VERSION 5.7 ;
  NOWIREEXTENSIONATPIN ON ;
  DIVIDERCHAR "/" ;
  BUSBITCHARS "[]" ;
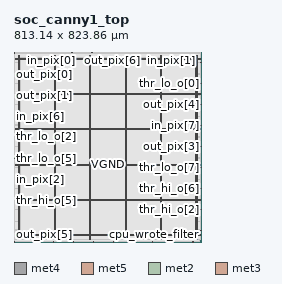
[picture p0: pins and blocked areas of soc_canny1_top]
MACRO soc_canny1_top
  CLASS BLOCK ;
  FOREIGN soc_canny1_top ;
  ORIGIN 0.000 0.000 ;
  SIZE 813.140 BY 823.860 ;
  PIN VGND
    DIRECTION INOUT ;
    USE GROUND ;
    PORT
      LAYER met4 ;
        RECT 24.340 10.640 25.940 810.800 ;
    END
    PORT
      LAYER met4 ;
        RECT 177.940 10.640 179.540 810.800 ;
    END
    PORT
      LAYER met4 ;
        RECT 331.540 10.640 333.140 810.800 ;
    END
    PORT
      LAYER met4 ;
        RECT 485.140 10.640 486.740 810.800 ;
    END
    PORT
      LAYER met4 ;
        RECT 638.740 10.640 640.340 810.800 ;
    END
    PORT
      LAYER met4 ;
        RECT 792.340 10.640 793.940 810.800 ;
    END
    PORT
      LAYER met5 ;
        RECT 5.280 30.030 807.540 31.630 ;
    END
    PORT
      LAYER met5 ;
        RECT 5.280 183.210 807.540 184.810 ;
    END
    PORT
      LAYER met5 ;
        RECT 5.280 336.390 807.540 337.990 ;
    END
    PORT
      LAYER met5 ;
        RECT 5.280 489.570 807.540 491.170 ;
    END
    PORT
      LAYER met5 ;
        RECT 5.280 642.750 807.540 644.350 ;
    END
    PORT
      LAYER met5 ;
        RECT 5.280 795.930 807.540 797.530 ;
    END
  END VGND
  PIN VPWR
    DIRECTION INOUT ;
    USE POWER ;
    PORT
      LAYER met4 ;
        RECT 21.040 10.640 22.640 810.800 ;
    END
    PORT
      LAYER met4 ;
        RECT 174.640 10.640 176.240 810.800 ;
    END
    PORT
      LAYER met4 ;
        RECT 328.240 10.640 329.840 810.800 ;
    END
    PORT
      LAYER met4 ;
        RECT 481.840 10.640 483.440 810.800 ;
    END
    PORT
      LAYER met4 ;
        RECT 635.440 10.640 637.040 810.800 ;
    END
    PORT
      LAYER met4 ;
        RECT 789.040 10.640 790.640 810.800 ;
    END
    PORT
      LAYER met5 ;
        RECT 5.280 26.730 807.540 28.330 ;
    END
    PORT
      LAYER met5 ;
        RECT 5.280 179.910 807.540 181.510 ;
    END
    PORT
      LAYER met5 ;
        RECT 5.280 333.090 807.540 334.690 ;
    END
    PORT
      LAYER met5 ;
        RECT 5.280 486.270 807.540 487.870 ;
    END
    PORT
      LAYER met5 ;
        RECT 5.280 639.450 807.540 641.050 ;
    END
    PORT
      LAYER met5 ;
        RECT 5.280 792.630 807.540 794.230 ;
    END
  END VPWR
  PIN clk
    DIRECTION INPUT ;
    USE SIGNAL ;
    ANTENNAGATEAREA 0.852000 ;
    PORT
      LAYER met2 ;
        RECT 431.570 0.000 431.850 4.000 ;
    END
  END clk
  PIN cpu_wrote_filter
    DIRECTION OUTPUT TRISTATE ;
    USE SIGNAL ;
    ANTENNADIFFAREA 0.795200 ;
    PORT
      LAYER met2 ;
        RECT 776.110 0.000 776.390 4.000 ;
    END
  END cpu_wrote_filter
  PIN in_pix[0]
    DIRECTION INPUT ;
    USE SIGNAL ;
    ANTENNAGATEAREA 0.126000 ;
    PORT
      LAYER met2 ;
        RECT 164.310 819.860 164.590 823.860 ;
    END
  END in_pix[0]
  PIN in_pix[1]
    DIRECTION INPUT ;
    USE SIGNAL ;
    ANTENNAGATEAREA 0.159000 ;
    PORT
      LAYER met2 ;
        RECT 682.730 819.860 683.010 823.860 ;
    END
  END in_pix[1]
  PIN in_pix[2]
    DIRECTION INPUT ;
    USE SIGNAL ;
    ANTENNAGATEAREA 0.213000 ;
    PORT
      LAYER met3 ;
        RECT 0.000 272.040 4.000 272.640 ;
    END
  END in_pix[2]
  PIN in_pix[3]
    DIRECTION INPUT ;
    USE SIGNAL ;
    ANTENNAGATEAREA 0.213000 ;
    PORT
      LAYER met2 ;
        RECT 257.690 0.000 257.970 4.000 ;
    END
  END in_pix[3]
  PIN in_pix[4]
    DIRECTION INPUT ;
    USE SIGNAL ;
    ANTENNAGATEAREA 0.247500 ;
    PORT
      LAYER met2 ;
        RECT 689.170 0.000 689.450 4.000 ;
    END
  END in_pix[4]
  PIN in_pix[5]
    DIRECTION INPUT ;
    USE SIGNAL ;
    ANTENNAGATEAREA 0.159000 ;
    PORT
      LAYER met2 ;
        RECT 595.790 819.860 596.070 823.860 ;
    END
  END in_pix[5]
  PIN in_pix[6]
    DIRECTION INPUT ;
    USE SIGNAL ;
    ANTENNAGATEAREA 0.213000 ;
    PORT
      LAYER met3 ;
        RECT 0.000 544.040 4.000 544.640 ;
    END
  END in_pix[6]
  PIN in_pix[7]
    DIRECTION INPUT ;
    USE SIGNAL ;
    ANTENNAGATEAREA 0.213000 ;
    PORT
      LAYER met3 ;
        RECT 809.140 506.640 813.140 507.240 ;
    END
  END in_pix[7]
  PIN in_valid
    DIRECTION INPUT ;
    USE SIGNAL ;
    ANTENNAGATEAREA 0.247500 ;
    PORT
      LAYER met2 ;
        RECT 512.070 819.860 512.350 823.860 ;
    END
  END in_valid
  PIN out_pix[0]
    DIRECTION OUTPUT TRISTATE ;
    USE SIGNAL ;
    ANTENNADIFFAREA 0.795200 ;
    PORT
      LAYER met3 ;
        RECT 0.000 727.640 4.000 728.240 ;
    END
  END out_pix[0]
  PIN out_pix[1]
    DIRECTION OUTPUT TRISTATE ;
    USE SIGNAL ;
    ANTENNADIFFAREA 0.795200 ;
    PORT
      LAYER met3 ;
        RECT 0.000 635.840 4.000 636.440 ;
    END
  END out_pix[1]
  PIN out_pix[2]
    DIRECTION OUTPUT TRISTATE ;
    USE SIGNAL ;
    ANTENNADIFFAREA 0.445500 ;
    PORT
      LAYER met3 ;
        RECT 809.140 51.040 813.140 51.640 ;
    END
  END out_pix[2]
  PIN out_pix[3]
    DIRECTION OUTPUT TRISTATE ;
    USE SIGNAL ;
    ANTENNADIFFAREA 0.445500 ;
    PORT
      LAYER met3 ;
        RECT 809.140 414.840 813.140 415.440 ;
    END
  END out_pix[3]
  PIN out_pix[4]
    DIRECTION OUTPUT TRISTATE ;
    USE SIGNAL ;
    ANTENNADIFFAREA 0.445500 ;
    PORT
      LAYER met3 ;
        RECT 809.140 595.040 813.140 595.640 ;
    END
  END out_pix[4]
  PIN out_pix[5]
    DIRECTION OUTPUT TRISTATE ;
    USE SIGNAL ;
    ANTENNADIFFAREA 0.795200 ;
    PORT
      LAYER met2 ;
        RECT 0.090 0.000 0.370 4.000 ;
    END
  END out_pix[5]
  PIN out_pix[6]
    DIRECTION OUTPUT TRISTATE ;
    USE SIGNAL ;
    ANTENNADIFFAREA 0.795200 ;
    PORT
      LAYER met2 ;
        RECT 425.130 819.860 425.410 823.860 ;
    END
  END out_pix[6]
  PIN out_pix[7]
    DIRECTION OUTPUT TRISTATE ;
    USE SIGNAL ;
    ANTENNADIFFAREA 0.795200 ;
    PORT
      LAYER met3 ;
        RECT 0.000 88.440 4.000 89.040 ;
    END
  END out_pix[7]
  PIN out_valid
    DIRECTION OUTPUT TRISTATE ;
    USE SIGNAL ;
    ANTENNADIFFAREA 0.795200 ;
    PORT
      LAYER met2 ;
        RECT 251.250 819.860 251.530 823.860 ;
    END
  END out_valid
  PIN resetn
    DIRECTION INPUT ;
    USE SIGNAL ;
    ANTENNAGATEAREA 0.742500 ;
    PORT
      LAYER met2 ;
        RECT 80.590 819.860 80.870 823.860 ;
    END
  END resetn
  PIN thr_hi_o[0]
    DIRECTION OUTPUT TRISTATE ;
    USE SIGNAL ;
    ANTENNADIFFAREA 0.795200 ;
    PORT
      LAYER met2 ;
        RECT 602.230 0.000 602.510 4.000 ;
    END
  END thr_hi_o[0]
  PIN thr_hi_o[1]
    DIRECTION OUTPUT TRISTATE ;
    USE SIGNAL ;
    ANTENNADIFFAREA 0.795200 ;
    PORT
      LAYER met2 ;
        RECT 769.670 819.860 769.950 823.860 ;
    END
  END thr_hi_o[1]
  PIN thr_hi_o[2]
    DIRECTION OUTPUT TRISTATE ;
    USE SIGNAL ;
    ANTENNADIFFAREA 0.445500 ;
    PORT
      LAYER met3 ;
        RECT 809.140 139.440 813.140 140.040 ;
    END
  END thr_hi_o[2]
  PIN thr_hi_o[3]
    DIRECTION OUTPUT TRISTATE ;
    USE SIGNAL ;
    ANTENNADIFFAREA 0.795200 ;
    PORT
      LAYER met2 ;
        RECT 83.810 0.000 84.090 4.000 ;
    END
  END thr_hi_o[3]
  PIN thr_hi_o[4]
    DIRECTION OUTPUT TRISTATE ;
    USE SIGNAL ;
    ANTENNADIFFAREA 0.795200 ;
    PORT
      LAYER met2 ;
        RECT 170.750 0.000 171.030 4.000 ;
    END
  END thr_hi_o[4]
  PIN thr_hi_o[5]
    DIRECTION OUTPUT TRISTATE ;
    USE SIGNAL ;
    ANTENNADIFFAREA 0.795200 ;
    PORT
      LAYER met3 ;
        RECT 0.000 180.240 4.000 180.840 ;
    END
  END thr_hi_o[5]
  PIN thr_hi_o[6]
    DIRECTION OUTPUT TRISTATE ;
    USE SIGNAL ;
    ANTENNADIFFAREA 0.445500 ;
    PORT
      LAYER met3 ;
        RECT 809.140 231.240 813.140 231.840 ;
    END
  END thr_hi_o[6]
  PIN thr_hi_o[7]
    DIRECTION OUTPUT TRISTATE ;
    USE SIGNAL ;
    ANTENNADIFFAREA 0.795200 ;
    PORT
      LAYER met2 ;
        RECT 344.630 0.000 344.910 4.000 ;
    END
  END thr_hi_o[7]
  PIN thr_lo_o[0]
    DIRECTION OUTPUT TRISTATE ;
    USE SIGNAL ;
    ANTENNADIFFAREA 0.445500 ;
    PORT
      LAYER met3 ;
        RECT 809.140 686.840 813.140 687.440 ;
    END
  END thr_lo_o[0]
  PIN thr_lo_o[1]
    DIRECTION OUTPUT TRISTATE ;
    USE SIGNAL ;
    ANTENNADIFFAREA 0.445500 ;
    PORT
      LAYER met3 ;
        RECT 809.140 778.640 813.140 779.240 ;
    END
  END thr_lo_o[1]
  PIN thr_lo_o[2]
    DIRECTION OUTPUT TRISTATE ;
    USE SIGNAL ;
    ANTENNADIFFAREA 0.795200 ;
    PORT
      LAYER met3 ;
        RECT 0.000 455.640 4.000 456.240 ;
    END
  END thr_lo_o[2]
  PIN thr_lo_o[3]
    DIRECTION OUTPUT TRISTATE ;
    USE SIGNAL ;
    ANTENNADIFFAREA 0.795200 ;
    PORT
      LAYER met2 ;
        RECT 338.190 819.860 338.470 823.860 ;
    END
  END thr_lo_o[3]
  PIN thr_lo_o[4]
    DIRECTION OUTPUT TRISTATE ;
    USE SIGNAL ;
    ANTENNADIFFAREA 0.795200 ;
    PORT
      LAYER met2 ;
        RECT 515.290 0.000 515.570 4.000 ;
    END
  END thr_lo_o[4]
  PIN thr_lo_o[5]
    DIRECTION OUTPUT TRISTATE ;
    USE SIGNAL ;
    ANTENNADIFFAREA 0.795200 ;
    PORT
      LAYER met3 ;
        RECT 0.000 363.840 4.000 364.440 ;
    END
  END thr_lo_o[5]
  PIN thr_lo_o[6]
    DIRECTION OUTPUT TRISTATE ;
    USE SIGNAL ;
    ANTENNADIFFAREA 0.795200 ;
    PORT
      LAYER met3 ;
        RECT 0.000 819.440 4.000 820.040 ;
    END
  END thr_lo_o[6]
  PIN thr_lo_o[7]
    DIRECTION OUTPUT TRISTATE ;
    USE SIGNAL ;
    ANTENNADIFFAREA 0.795200 ;
    PORT
      LAYER met3 ;
        RECT 809.140 323.040 813.140 323.640 ;
    END
  END thr_lo_o[7]
  OBS
      LAYER li1 ;
        RECT 5.520 10.795 807.300 810.645 ;
      LAYER met1 ;
        RECT 0.070 10.640 807.300 810.800 ;
      LAYER met2 ;
        RECT 0.100 819.580 80.310 820.490 ;
        RECT 81.150 819.580 164.030 820.490 ;
        RECT 164.870 819.580 250.970 820.490 ;
        RECT 251.810 819.580 337.910 820.490 ;
        RECT 338.750 819.580 424.850 820.490 ;
        RECT 425.690 819.580 511.790 820.490 ;
        RECT 512.630 819.580 595.510 820.490 ;
        RECT 596.350 819.580 682.450 820.490 ;
        RECT 683.290 819.580 769.390 820.490 ;
        RECT 770.230 819.580 805.370 820.490 ;
        RECT 0.100 4.280 805.370 819.580 ;
        RECT 0.650 3.670 83.530 4.280 ;
        RECT 84.370 3.670 170.470 4.280 ;
        RECT 171.310 3.670 257.410 4.280 ;
        RECT 258.250 3.670 344.350 4.280 ;
        RECT 345.190 3.670 431.290 4.280 ;
        RECT 432.130 3.670 515.010 4.280 ;
        RECT 515.850 3.670 601.950 4.280 ;
        RECT 602.790 3.670 688.890 4.280 ;
        RECT 689.730 3.670 775.830 4.280 ;
        RECT 776.670 3.670 805.370 4.280 ;
      LAYER met3 ;
        RECT 4.400 819.040 809.140 819.905 ;
        RECT 3.990 779.640 809.140 819.040 ;
        RECT 3.990 778.240 808.740 779.640 ;
        RECT 3.990 728.640 809.140 778.240 ;
        RECT 4.400 727.240 809.140 728.640 ;
        RECT 3.990 687.840 809.140 727.240 ;
        RECT 3.990 686.440 808.740 687.840 ;
        RECT 3.990 636.840 809.140 686.440 ;
        RECT 4.400 635.440 809.140 636.840 ;
        RECT 3.990 596.040 809.140 635.440 ;
        RECT 3.990 594.640 808.740 596.040 ;
        RECT 3.990 545.040 809.140 594.640 ;
        RECT 4.400 543.640 809.140 545.040 ;
        RECT 3.990 507.640 809.140 543.640 ;
        RECT 3.990 506.240 808.740 507.640 ;
        RECT 3.990 456.640 809.140 506.240 ;
        RECT 4.400 455.240 809.140 456.640 ;
        RECT 3.990 415.840 809.140 455.240 ;
        RECT 3.990 414.440 808.740 415.840 ;
        RECT 3.990 364.840 809.140 414.440 ;
        RECT 4.400 363.440 809.140 364.840 ;
        RECT 3.990 324.040 809.140 363.440 ;
        RECT 3.990 322.640 808.740 324.040 ;
        RECT 3.990 273.040 809.140 322.640 ;
        RECT 4.400 271.640 809.140 273.040 ;
        RECT 3.990 232.240 809.140 271.640 ;
        RECT 3.990 230.840 808.740 232.240 ;
        RECT 3.990 181.240 809.140 230.840 ;
        RECT 4.400 179.840 809.140 181.240 ;
        RECT 3.990 140.440 809.140 179.840 ;
        RECT 3.990 139.040 808.740 140.440 ;
        RECT 3.990 89.440 809.140 139.040 ;
        RECT 4.400 88.040 809.140 89.440 ;
        RECT 3.990 52.040 809.140 88.040 ;
        RECT 3.990 50.640 808.740 52.040 ;
        RECT 3.990 10.715 809.140 50.640 ;
      LAYER met4 ;
        RECT 19.615 33.495 20.640 800.865 ;
        RECT 23.040 33.495 23.940 800.865 ;
        RECT 26.340 33.495 174.240 800.865 ;
        RECT 176.640 33.495 177.540 800.865 ;
        RECT 179.940 33.495 327.840 800.865 ;
        RECT 330.240 33.495 331.140 800.865 ;
        RECT 333.540 33.495 481.440 800.865 ;
        RECT 483.840 33.495 484.740 800.865 ;
        RECT 487.140 33.495 635.040 800.865 ;
        RECT 637.440 33.495 638.340 800.865 ;
        RECT 640.740 33.495 786.305 800.865 ;
  END
END soc_canny1_top
END LIBRARY

